VERSION 5.7 ;
  NAMESCASESENSITIVE ON ;
  NOWIREEXTENSIONATPIN ON ;
  DIVIDERCHAR "/" ;
  BUSBITCHARS "[]" ;
UNITS
  DATABASE MICRONS 200 ;
END UNITS

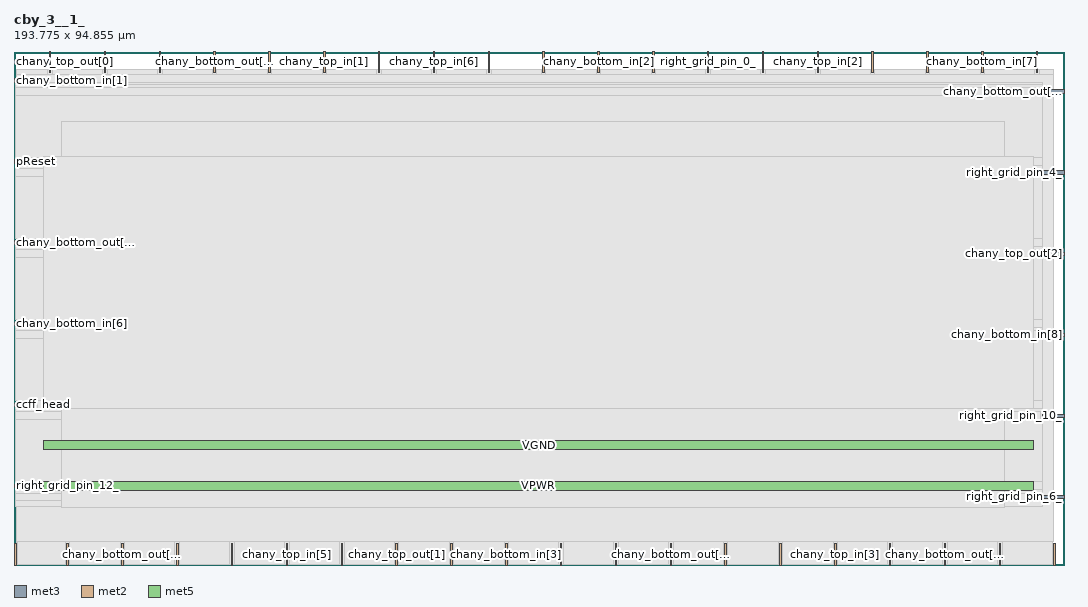
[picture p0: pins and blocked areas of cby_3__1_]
MACRO cby_3__1_
  CLASS BLOCK ;
  FOREIGN cby_3__1_ ;
  ORIGIN 0.000 0.000 ;
  SIZE 193.775 BY 94.855 ;
  PIN ccff_head
    DIRECTION INPUT ;
    PORT
      LAYER met3 ;
        RECT 0.000 29.280 4.000 29.880 ;
    END
  END ccff_head
  PIN ccff_tail
    DIRECTION OUTPUT TRISTATE ;
    PORT
      LAYER met2 ;
        RECT 47.010 90.855 47.290 94.855 ;
    END
  END ccff_tail
  PIN chany_bottom_in[0]
    DIRECTION INPUT ;
    PORT
      LAYER met2 ;
        RECT 26.770 90.855 27.050 94.855 ;
    END
  END chany_bottom_in[0]
  PIN chany_bottom_in[1]
    DIRECTION INPUT ;
    PORT
      LAYER met3 ;
        RECT 0.000 89.120 4.000 89.720 ;
    END
  END chany_bottom_in[1]
  PIN chany_bottom_in[2]
    DIRECTION INPUT ;
    PORT
      LAYER met2 ;
        RECT 107.730 90.855 108.010 94.855 ;
    END
  END chany_bottom_in[2]
  PIN chany_bottom_in[3]
    DIRECTION INPUT ;
    PORT
      LAYER met2 ;
        RECT 90.710 0.000 90.990 4.000 ;
    END
  END chany_bottom_in[3]
  PIN chany_bottom_in[4]
    DIRECTION INPUT ;
    PORT
      LAYER met2 ;
        RECT 110.950 0.000 111.230 4.000 ;
    END
  END chany_bottom_in[4]
  PIN chany_bottom_in[5]
    DIRECTION INPUT ;
    PORT
      LAYER met2 ;
        RECT 87.490 90.855 87.770 94.855 ;
    END
  END chany_bottom_in[5]
  PIN chany_bottom_in[6]
    DIRECTION INPUT ;
    PORT
      LAYER met3 ;
        RECT 0.000 44.240 4.000 44.840 ;
    END
  END chany_bottom_in[6]
  PIN chany_bottom_in[7]
    DIRECTION INPUT ;
    PORT
      LAYER met2 ;
        RECT 178.570 90.855 178.850 94.855 ;
    END
  END chany_bottom_in[7]
  PIN chany_bottom_in[8]
    DIRECTION INPUT ;
    PORT
      LAYER met3 ;
        RECT 189.775 42.200 193.775 42.800 ;
    END
  END chany_bottom_in[8]
  PIN chany_bottom_out[0]
    DIRECTION OUTPUT TRISTATE ;
    PORT
      LAYER met2 ;
        RECT 16.650 90.855 16.930 94.855 ;
    END
  END chany_bottom_out[0]
  PIN chany_bottom_out[1]
    DIRECTION OUTPUT TRISTATE ;
    PORT
      LAYER met2 ;
        RECT 121.070 0.000 121.350 4.000 ;
    END
  END chany_bottom_out[1]
  PIN chany_bottom_out[2]
    DIRECTION OUTPUT TRISTATE ;
    PORT
      LAYER met2 ;
        RECT 36.890 90.855 37.170 94.855 ;
    END
  END chany_bottom_out[2]
  PIN chany_bottom_out[3]
    DIRECTION OUTPUT TRISTATE ;
    PORT
      LAYER met2 ;
        RECT 117.850 90.855 118.130 94.855 ;
    END
  END chany_bottom_out[3]
  PIN chany_bottom_out[4]
    DIRECTION OUTPUT TRISTATE ;
    PORT
      LAYER met2 ;
        RECT 19.870 0.000 20.150 4.000 ;
    END
  END chany_bottom_out[4]
  PIN chany_bottom_out[5]
    DIRECTION OUTPUT TRISTATE ;
    PORT
      LAYER met2 ;
        RECT 171.670 0.000 171.950 4.000 ;
    END
  END chany_bottom_out[5]
  PIN chany_bottom_out[6]
    DIRECTION OUTPUT TRISTATE ;
    PORT
      LAYER met3 ;
        RECT 0.000 59.200 4.000 59.800 ;
    END
  END chany_bottom_out[6]
  PIN chany_bottom_out[7]
    DIRECTION OUTPUT TRISTATE ;
    PORT
      LAYER met2 ;
        RECT 191.910 0.000 192.190 4.000 ;
    END
  END chany_bottom_out[7]
  PIN chany_bottom_out[8]
    DIRECTION OUTPUT TRISTATE ;
    PORT
      LAYER met3 ;
        RECT 189.775 87.080 193.775 87.680 ;
    END
  END chany_bottom_out[8]
  PIN chany_top_in[0]
    DIRECTION INPUT ;
    PORT
      LAYER met2 ;
        RECT 161.550 0.000 161.830 4.000 ;
    END
  END chany_top_in[0]
  PIN chany_top_in[1]
    DIRECTION INPUT ;
    PORT
      LAYER met2 ;
        RECT 57.130 90.855 57.410 94.855 ;
    END
  END chany_top_in[1]
  PIN chany_top_in[2]
    DIRECTION INPUT ;
    PORT
      LAYER met2 ;
        RECT 148.210 90.855 148.490 94.855 ;
    END
  END chany_top_in[2]
  PIN chany_top_in[3]
    DIRECTION INPUT ;
    PORT
      LAYER met2 ;
        RECT 151.430 0.000 151.710 4.000 ;
    END
  END chany_top_in[3]
  PIN chany_top_in[4]
    DIRECTION INPUT ;
    PORT
      LAYER met2 ;
        RECT 97.610 90.855 97.890 94.855 ;
    END
  END chany_top_in[4]
  PIN chany_top_in[5]
    DIRECTION INPUT ;
    PORT
      LAYER met2 ;
        RECT 50.230 0.000 50.510 4.000 ;
    END
  END chany_top_in[5]
  PIN chany_top_in[6]
    DIRECTION INPUT ;
    PORT
      LAYER met2 ;
        RECT 77.370 90.855 77.650 94.855 ;
    END
  END chany_top_in[6]
  PIN chany_top_in[7]
    DIRECTION INPUT ;
    PORT
      LAYER met2 ;
        RECT 141.310 0.000 141.590 4.000 ;
    END
  END chany_top_in[7]
  PIN chany_top_in[8]
    DIRECTION INPUT ;
    PORT
      LAYER met2 ;
        RECT 168.450 90.855 168.730 94.855 ;
    END
  END chany_top_in[8]
  PIN chany_top_out[0]
    DIRECTION OUTPUT TRISTATE ;
    PORT
      LAYER met2 ;
        RECT 6.530 90.855 6.810 94.855 ;
    END
  END chany_top_out[0]
  PIN chany_top_out[1]
    DIRECTION OUTPUT TRISTATE ;
    PORT
      LAYER met2 ;
        RECT 70.470 0.000 70.750 4.000 ;
    END
  END chany_top_out[1]
  PIN chany_top_out[2]
    DIRECTION OUTPUT TRISTATE ;
    PORT
      LAYER met3 ;
        RECT 189.775 57.160 193.775 57.760 ;
    END
  END chany_top_out[2]
  PIN chany_top_out[3]
    DIRECTION OUTPUT TRISTATE ;
    PORT
      LAYER met2 ;
        RECT 158.330 90.855 158.610 94.855 ;
    END
  END chany_top_out[3]
  PIN chany_top_out[4]
    DIRECTION OUTPUT TRISTATE ;
    PORT
      LAYER met2 ;
        RECT 188.690 90.855 188.970 94.855 ;
    END
  END chany_top_out[4]
  PIN chany_top_out[5]
    DIRECTION OUTPUT TRISTATE ;
    PORT
      LAYER met2 ;
        RECT 181.790 0.000 182.070 4.000 ;
    END
  END chany_top_out[5]
  PIN chany_top_out[6]
    DIRECTION OUTPUT TRISTATE ;
    PORT
      LAYER met2 ;
        RECT 40.110 0.000 40.390 4.000 ;
    END
  END chany_top_out[6]
  PIN chany_top_out[7]
    DIRECTION OUTPUT TRISTATE ;
    PORT
      LAYER met2 ;
        RECT 29.990 0.000 30.270 4.000 ;
    END
  END chany_top_out[7]
  PIN chany_top_out[8]
    DIRECTION OUTPUT TRISTATE ;
    PORT
      LAYER met2 ;
        RECT 131.190 0.000 131.470 4.000 ;
    END
  END chany_top_out[8]
  PIN left_grid_pin_1_
    DIRECTION OUTPUT TRISTATE ;
    PORT
      LAYER met2 ;
        RECT 100.830 0.000 101.110 4.000 ;
    END
  END left_grid_pin_1_
  PIN left_grid_pin_5_
    DIRECTION OUTPUT TRISTATE ;
    PORT
      LAYER met2 ;
        RECT 80.590 0.000 80.870 4.000 ;
    END
  END left_grid_pin_5_
  PIN left_grid_pin_9_
    DIRECTION OUTPUT TRISTATE ;
    PORT
      LAYER met2 ;
        RECT 60.350 0.000 60.630 4.000 ;
    END
  END left_grid_pin_9_
  PIN pReset
    DIRECTION INPUT ;
    PORT
      LAYER met3 ;
        RECT 0.000 74.160 4.000 74.760 ;
    END
  END pReset
  PIN prog_clk
    DIRECTION INPUT ;
    PORT
      LAYER met2 ;
        RECT 9.750 0.000 10.030 4.000 ;
    END
  END prog_clk
  PIN right_grid_pin_0_
    DIRECTION OUTPUT TRISTATE ;
    PORT
      LAYER met2 ;
        RECT 127.970 90.855 128.250 94.855 ;
    END
  END right_grid_pin_0_
  PIN right_grid_pin_10_
    DIRECTION OUTPUT TRISTATE ;
    PORT
      LAYER met3 ;
        RECT 189.775 27.240 193.775 27.840 ;
    END
  END right_grid_pin_10_
  PIN right_grid_pin_12_
    DIRECTION OUTPUT TRISTATE ;
    PORT
      LAYER met3 ;
        RECT 0.000 14.320 4.000 14.920 ;
    END
  END right_grid_pin_12_
  PIN right_grid_pin_14_
    DIRECTION OUTPUT TRISTATE ;
    PORT
      LAYER met2 ;
        RECT 67.250 90.855 67.530 94.855 ;
    END
  END right_grid_pin_14_
  PIN right_grid_pin_2_
    DIRECTION OUTPUT TRISTATE ;
    PORT
      LAYER met2 ;
        RECT 138.090 90.855 138.370 94.855 ;
    END
  END right_grid_pin_2_
  PIN right_grid_pin_4_
    DIRECTION OUTPUT TRISTATE ;
    PORT
      LAYER met3 ;
        RECT 189.775 72.120 193.775 72.720 ;
    END
  END right_grid_pin_4_
  PIN right_grid_pin_6_
    DIRECTION OUTPUT TRISTATE ;
    PORT
      LAYER met3 ;
        RECT 189.775 12.280 193.775 12.880 ;
    END
  END right_grid_pin_6_
  PIN right_grid_pin_8_
    DIRECTION OUTPUT TRISTATE ;
    PORT
      LAYER met2 ;
        RECT 0.090 0.000 0.370 4.000 ;
    END
  END right_grid_pin_8_
  PIN VPWR
    DIRECTION INPUT ;
    USE POWER ;
    PORT
      LAYER met5 ;
        RECT 5.520 13.840 188.140 15.440 ;
    END
  END VPWR
  PIN VGND
    DIRECTION INPUT ;
    USE GROUND ;
    PORT
      LAYER met5 ;
        RECT 5.520 21.340 188.140 22.940 ;
    END
  END VGND
  OBS
      LAYER li1 ;
        RECT 5.520 10.795 188.140 81.685 ;
      LAYER met1 ;
        RECT 0.530 0.040 190.830 91.420 ;
      LAYER met2 ;
        RECT 0.370 90.575 6.250 91.530 ;
        RECT 7.090 90.575 16.370 91.530 ;
        RECT 17.210 90.575 26.490 91.530 ;
        RECT 27.330 90.575 36.610 91.530 ;
        RECT 37.450 90.575 46.730 91.530 ;
        RECT 47.570 90.575 56.850 91.530 ;
        RECT 57.690 90.575 66.970 91.530 ;
        RECT 67.810 90.575 77.090 91.530 ;
        RECT 77.930 90.575 87.210 91.530 ;
        RECT 88.050 90.575 97.330 91.530 ;
        RECT 98.170 90.575 107.450 91.530 ;
        RECT 108.290 90.575 117.570 91.530 ;
        RECT 118.410 90.575 127.690 91.530 ;
        RECT 128.530 90.575 137.810 91.530 ;
        RECT 138.650 90.575 147.930 91.530 ;
        RECT 148.770 90.575 158.050 91.530 ;
        RECT 158.890 90.575 168.170 91.530 ;
        RECT 169.010 90.575 178.290 91.530 ;
        RECT 179.130 90.575 188.410 91.530 ;
        RECT 189.250 90.575 191.910 91.530 ;
        RECT 0.370 4.280 191.910 90.575 ;
        RECT 0.650 0.010 9.470 4.280 ;
        RECT 10.310 0.010 19.590 4.280 ;
        RECT 20.430 0.010 29.710 4.280 ;
        RECT 30.550 0.010 39.830 4.280 ;
        RECT 40.670 0.010 49.950 4.280 ;
        RECT 50.790 0.010 60.070 4.280 ;
        RECT 60.910 0.010 70.190 4.280 ;
        RECT 71.030 0.010 80.310 4.280 ;
        RECT 81.150 0.010 90.430 4.280 ;
        RECT 91.270 0.010 100.550 4.280 ;
        RECT 101.390 0.010 110.670 4.280 ;
        RECT 111.510 0.010 120.790 4.280 ;
        RECT 121.630 0.010 130.910 4.280 ;
        RECT 131.750 0.010 141.030 4.280 ;
        RECT 141.870 0.010 151.150 4.280 ;
        RECT 151.990 0.010 161.270 4.280 ;
        RECT 162.110 0.010 171.390 4.280 ;
        RECT 172.230 0.010 181.510 4.280 ;
        RECT 182.350 0.010 191.630 4.280 ;
      LAYER met3 ;
        RECT 4.400 88.720 189.775 89.120 ;
        RECT 0.310 88.080 189.775 88.720 ;
        RECT 0.310 86.680 189.375 88.080 ;
        RECT 0.310 75.160 189.775 86.680 ;
        RECT 4.400 73.760 189.775 75.160 ;
        RECT 0.310 73.120 189.775 73.760 ;
        RECT 0.310 71.720 189.375 73.120 ;
        RECT 0.310 60.200 189.775 71.720 ;
        RECT 4.400 58.800 189.775 60.200 ;
        RECT 0.310 58.160 189.775 58.800 ;
        RECT 0.310 56.760 189.375 58.160 ;
        RECT 0.310 45.240 189.775 56.760 ;
        RECT 4.400 43.840 189.775 45.240 ;
        RECT 0.310 43.200 189.775 43.840 ;
        RECT 0.310 41.800 189.375 43.200 ;
        RECT 0.310 30.280 189.775 41.800 ;
        RECT 4.400 28.880 189.775 30.280 ;
        RECT 0.310 28.240 189.775 28.880 ;
        RECT 0.310 26.840 189.375 28.240 ;
        RECT 0.310 15.320 189.775 26.840 ;
        RECT 4.400 13.920 189.775 15.320 ;
        RECT 0.310 13.280 189.775 13.920 ;
        RECT 0.310 11.880 189.375 13.280 ;
        RECT 0.310 10.715 189.775 11.880 ;
      LAYER met4 ;
        RECT 8.720 10.640 182.820 81.840 ;
      LAYER met5 ;
        RECT 5.520 28.840 188.140 75.440 ;
  END
END cby_3__1_
END LIBRARY

